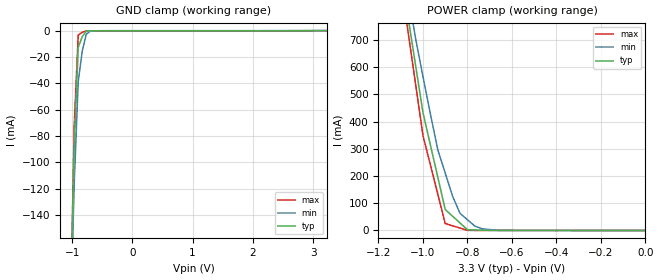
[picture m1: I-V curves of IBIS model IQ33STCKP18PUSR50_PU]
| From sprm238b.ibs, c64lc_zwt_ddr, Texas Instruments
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|   Model Cell IQ33STCKP18PUSR50
[Model]   IQ33STCKP18PUSR50_PU
Model_type   Input
Polarity   Non-Inverting
Vinl =  0.8V
Vinh =  2V
C_comp   0.7641276p   0.7005841p   0.8387284p
[Model Spec]
Vinl   0.8V   0.8V   0.8V
Vinh   2V   2V   2V
[Temperature Range]   25   125   -40
[Voltage Range]   3.3   3.14   3.47
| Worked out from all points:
|   GND clamp passes 1 mA (typ) near -0.78 V on its own axis
|   POWER clamp passes 1 mA (typ) near -0.73 V on its own axis
[POWER_clamp]
|   voltage   I(typ)   I(min)   I(max)
-3.3V     15.05A     13.64A     16.17A
-1.067V   781.2mA    866.5mA    727.6mA
-1.033V   606.9mA    705.9mA    538mA
-1V       432.7mA    564.8mA    348.4mA
-933.3mV  195.4mA    296.2mA    133.1mA
-900mV    76.75mA    210.7mA    25.46mA
-866.7mV  52.11mA    125.2mA    17.11mA
-833.3mV  27.48mA    62.71mA    8.767mA
-800mV    2.836mA    39.32mA    419.2uA
-766.7mV  1.946mA    15.94mA    332.1uA
-733.3mV  1.057mA    5.981mA    245uA
-11.55fV  95.23nA    127.8nA    222.7nA
[GND_clamp]
|   voltage   I(typ)   I(min)   I(max)
-3.3V     -17.3A     -15.65A    -18.51A
-1.033V   -224.7mA   -230.5mA   -227.6mA
-966.7mV  -89.48mA   -116.8mA   -72.36mA
-900mV    -12.72mA   -38.89mA   -3.485mA
-833.3mV  -4.628mA   -15.63mA   -1.34mA
-766.7mV  -440.3uA   -2.832mA   -254uA
-700mV    -155.6uA   -497.2uA   -226.5uA
3.233V    -8.718uA   7.659uA    -45.2uA
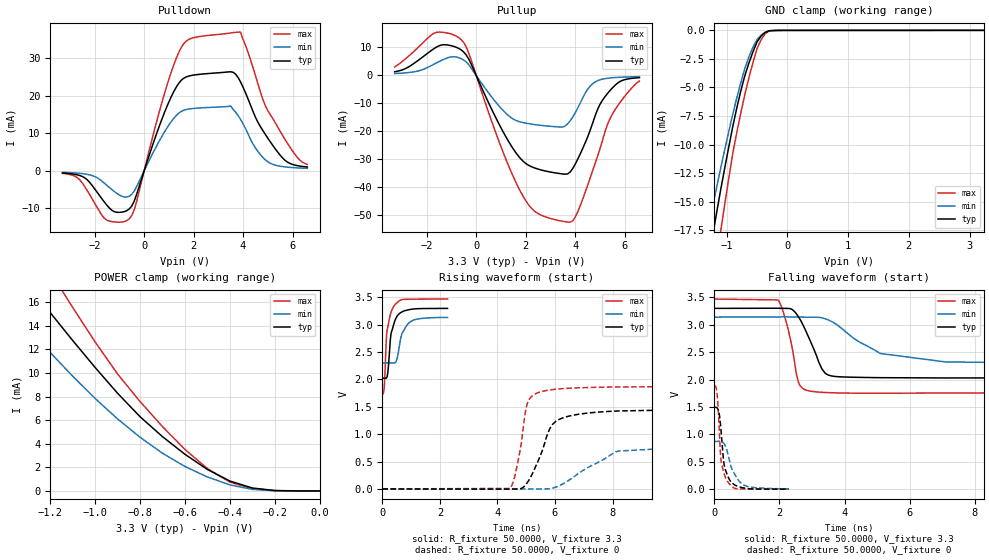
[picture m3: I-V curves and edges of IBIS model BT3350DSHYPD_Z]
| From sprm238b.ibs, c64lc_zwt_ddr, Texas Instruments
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|   Model Cell BT3350DSHYPDFZSCP18
[Model]   BT3350DSHYPD_Z
Model_type   I/O
Polarity   Non-Inverting
Enable   Active-Low
Vinl =  0.8V
Vinh =  2V
Cref =  15.0000pF
Rref =  100.0000M
Vref =  0V
Vmeas =  1.65
C_comp   1.471252p   1.436254p   1.510805p
[Model Spec]
Vinl   0.8V   0.8V   0.8V
Vinh   2V   2V   2V
[Temperature Range]   25   125   -40
[Voltage Range]   3.3   3.14   3.47
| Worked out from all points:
|   slope of the pulldown table from 0 to 0.495 V, typ, clamps not added: 50.8 ohm
|   slope of the pullup table from 0 to 0.495 V, typ, clamps not added: 51.2 ohm
|   GND clamp passes 1 mA (typ) near -0.50 V on its own axis
|   POWER clamp passes 1 mA (typ) near -0.42 V on its own axis
|   rising waveform, R_fixture 50.0000, V_fixture 3.3: 20-80 % time 199ps typ, 278ps min, 162ps max; typ from 2.02 V to 3.3 V
|   rising waveform, R_fixture 50.0000, V_fixture 0: 20-80 % time 704ps typ, 1.65ns min, 350ps max; typ from 0 V to 1.49 V
|   falling waveform, R_fixture 50.0000, V_fixture 3.3: 20-80 % time 549ps typ, 1.47ns min, 355ps max; typ from 3.3 V to 2.04 V
|   falling waveform, R_fixture 50.0000, V_fixture 0: 20-80 % time 187ps typ, 329ps min, 145ps max; typ from 1.49 V to 0.001 V
[POWER_clamp]
|   voltage   I(typ)   I(min)   I(max)
-3.3V     77.67mA    57.5mA     94.63mA
-1.433V   21.11mA    16.7mA     25.79mA
-1.267V   16.76mA    13.13mA    20.62mA
-1.233V   15.94mA    12.43mA    19.6mA
-1.133V   13.55mA    10.4mA     16.57mA
-900mV    8.283mA    6.107mA    9.918mA
-800mV    6.297mA    4.554mA    7.585mA
-600mV    3.11mA     2.075mA    3.521mA
-500mV    1.823mA    1.185mA    1.894mA
-400mV    839.2uA    515.2uA    752.3uA
-300mV    250.4uA    130.7uA    193.1uA
0V        112.2nA    206.3nA    236nA
[Pulldown]
|   voltage   I(typ)   I(min)   I(max)
-3.3V     -544.2uA   -373.8uA   -649.3uA
-2.6V     -1.226mA   -645.1uA   -2.397mA
-1.5V     -9.17mA    -3.874mA   -13.14mA
-600mV    -10.12mA   -6.728mA   -12.73mA
-300mV    -6.174mA   -4.15mA    -8.053mA
900mV     16.8mA     11.19mA    22.28mA
1.5V      24.11mA    15.83mA    32.83mA
3.5V      26.39mA    17.27mA    36.71mA
3.8V      24.86mA    14.73mA    36.94mA
5V        8.732mA    2.435mA    16.05mA
5.8V      2.332mA    999.4uA    7.304mA
6.6V      1.052mA    693.5uA    1.743mA
[Pullup]
|   voltage   I(typ)   I(min)   I(max)
-3.3V     1.324mA    694.3uA    3.024mA
-1.7V     9.62mA     4.052mA    15.11mA
-600mV    9.081mA    5.972mA    12.73mA
1.1V      -20.32mA   -12.63mA   -27.71mA
1.9V      -30.67mA   -16.84mA   -43.22mA
2.5V      -33.44mA   -17.7mA    -49.34mA
3.7V      -35.15mA   -17.28mA   -52.38mA
4.1V      -30.02mA   -11.73mA   -48.83mA
4.6V      -19.78mA   -3.879mA   -36.8mA
5.2V      -7.671mA   -1.145mA   -20.29mA
5.7V      -2.836mA   -700.2uA   -11.11mA
6.6V      -790.1uA   -430.1uA   -2.018mA
[GND_clamp]
|   voltage   I(typ)   I(min)   I(max)
-3.3V     -92.33mA   -69.21mA   -111.6mA
-1.3V     -20.3mA    -17.23mA   -25.02mA
-1.233V   -18.14mA   -15.52mA   -22.55mA
-1.167V   -16.05mA   -13.82mA   -20.11mA
-1.1V     -14.04mA   -12.14mA   -17.68mA
-1.033V   -12.14mA   -10.52mA   -15.33mA
-900mV    -8.477mA   -7.373mA   -10.83mA
-700mV    -3.973mA   -3.332mA   -5.632mA
-500mV    -1.023mA   -808.8uA   -1.617mA
-366.7mV  -182.4uA   -178uA     -312.5uA
-166.7mV  -5.407uA   -6.465uA   -7.339uA
3.233V    80.37nA    2.438uA    206.3nA
[Ramp]
| variable   typ   min   max
dV/dt_f  0.7706559/0.5578093n  0.5145686/1.324064n   1.049533/0.3598343n
dV/dt_r  0.8978218/0.705227n   0.5229636/1.669374n   1.137822/0.3496418n
R_load = 50
[Rising Waveform]
R_fixture = 50.0000
V_fixture = 3.3
V_fixture_min = 3.14
V_fixture_max = 3.47
|   time   V(typ)   V(min)   V(max)
0s        2.024V     2.301V     1.734V
60ps      2.025V     2.303V     1.831V
135ps     2.025V     2.304V     2.705V
165ps     2.051V     2.304V     2.905V
285ps     2.769V     2.303V     3.2V
405ps     3.027V     2.301V     3.343V
510ps     3.155V     2.377V     3.404V
675ps     3.234V     2.828V     3.459V
930ps     3.275V     3.037V     3.467V
2.265ns   3.298V     3.134V     3.47V
[Rising Waveform]
R_fixture = 50.0000
V_fixture = 0
V_fixture_min = 0
V_fixture_max = 0
|   time   V(typ)   V(min)   V(max)
0s        52.07uV    29.49uV    82.73uV
4.425ns   -3.357mV   -74.75uV   9.199mV
4.635ns   -151.3uV   -2.371mV   307.6mV
4.995ns   84.47mV    -1.111mV   1.471V
5.13ns    194.3mV    -533.3uV   1.657V
5.91ns    1.178V     12.48mV    1.815V
7.035ns   1.38V      358.3mV    1.852V
8.175ns   1.425V     691.2mV    1.863V
17.13ns   1.474V     845.3mV    1.877V
115.7ns   1.487V     863.9mV    1.889V
[Falling Waveform]
R_fixture = 50.0000
V_fixture = 3.3
V_fixture_min = 3.14
V_fixture_max = 3.47
|   time   V(typ)   V(min)   V(max)
0s        3.3V       3.14V      3.47V
1.95ns    3.303V     3.143V     3.454V
2.25ns    3.299V     3.145V     2.953V
2.535ns   3.189V     3.141V     2.061V
2.61ns    3.122V     3.141V     1.914V
2.82ns    2.874V     3.14V      1.808V
3.405ns   2.116V     3.11V      1.765V
5.1ns     2.035V     2.477V     1.751V
7.11ns    2.03V      2.322V     1.755V
53.46ns   2.041V     2.291V     1.741V
[Falling Waveform]
R_fixture = 50.0000
V_fixture = 0
V_fixture_min = 0
V_fixture_max = 0
|   time   V(typ)   V(min)   V(max)
0s        1.493V     871.2mV    1.89V
60ps      1.491V     871.7mV    1.832V
90ps      1.477V     872.6mV    1.679V
150ps     1.362V     873.4mV    1.057V
210ps     1.02V      867mV      488.6mV
300ps     438.5mV    826mV      278.3mV
435ps     204.6mV    590.3mV    114.7mV
570ps     99.71mV    326.4mV    32.75mV
900ps     23mV       75.78mV    3.103mV
2.28ns    1.496mV    6.592mV    353.5uV
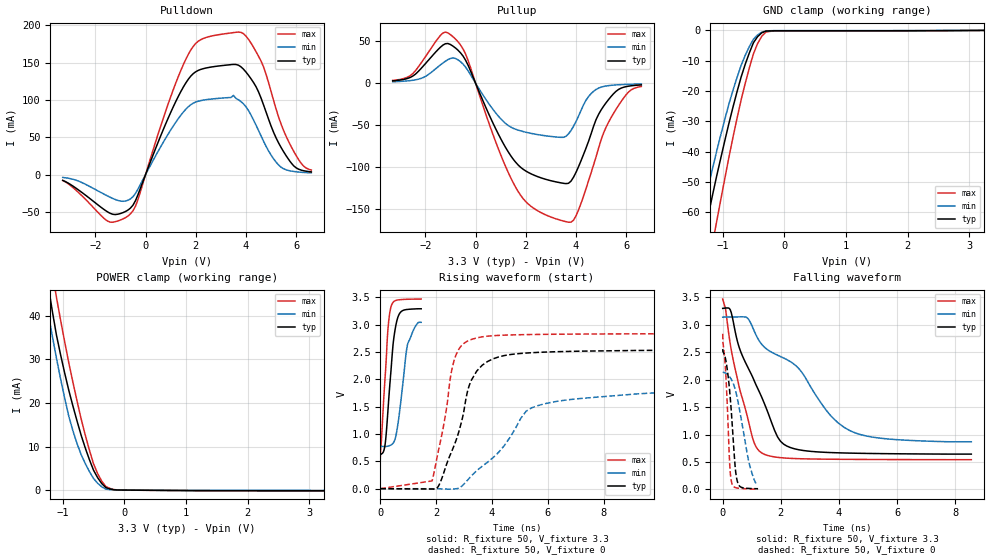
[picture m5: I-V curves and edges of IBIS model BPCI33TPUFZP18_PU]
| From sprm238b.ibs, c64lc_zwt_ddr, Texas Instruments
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|   Model Cell BPCI33TPUFZP18
[Model]   BPCI33TPUFZP18_PU
Model_type   I/O
Polarity   Non-Inverting
Enable   Active-Low
Vinl =  0.8
Vinh =  2.0
Cref =  10.0000pF
Rref =  50.0000
Vref =  1.5V
Vmeas =  1.5
C_comp   3.402036p   3.350014p   3.525193p
[Temperature Range]   25   125   -40
[Voltage Range]   3.3   3.14   3.47
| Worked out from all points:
|   slope of the pulldown table from 0 to 0.495 V, typ, clamps not added: 11.5 ohm
|   slope of the pullup table from 0 to 0.495 V, typ, clamps not added: 14.2 ohm
|   GND clamp passes 1 mA (typ) near -0.38 V on its own axis
|   POWER clamp passes 1 mA (typ) near -0.33 V on its own axis
|   rising waveform, R_fixture 50, V_fixture 3.3: 20-80 % time 250ps typ, 312ps min, 202ps max; typ from 0.62 V to 3.29 V
|   rising waveform, R_fixture 50, V_fixture 0: 20-80 % time 911ps typ, 3.2ns min, 574ps max; typ from 0.001 V to 2.56 V
|   falling waveform, R_fixture 50, V_fixture 3.3: 20-80 % time 1.24ns typ, 2.47ns min, 742ps max; typ from 3.3 V to 0.644 V
|   falling waveform, R_fixture 50, V_fixture 0: 20-80 % time 223ps typ, 423ps min, 145ps max; typ from 2.56 V to 0.014 V
[POWER_clamp]
|   voltage   I(typ)   I(min)   I(max)
-3.3V     268.4mA    207.5mA    327.8mA
-1.3V     53.47mA    45.85mA    64.24mA
-1.233V   47.03mA    40.57mA    56.88mA
-1.167V   41.08mA    35.39mA    50.23mA
-1.1V     35.61mA    30.31mA    44.28mA
-900mV    22.93mA    16.96mA    29.25mA
-700mV    12.61mA    8.149mA    16.37mA
-500mV    4.606mA    2.687mA    6.094mA
-366.7mV  1.523mA    761.7uA    2.069mA
-300mV    577.1uA    229.5uA    834.2uA
-100mV    16.91uA    10.09uA    24.41uA
3.233V    -147.1uA   -77.91uA   -202.4uA
[Pulldown]
|   voltage   I(typ)   I(min)   I(max)
-3.3V     -7.786mA   -3.889mA   -7.984mA
-1.5V     -50.3mA    -28.94mA   -62.59mA
-700mV    -47.57mA   -34.42mA   -55.54mA
-400mV    -34.9mA    -25.14mA   -42.3mA
900mV     75.57mA    54.22mA    94.66mA
1.8V      131.8mA    93.47mA    166.8mA
2.3V      141.8mA    99.68mA    182.3mA
3.7V      146.4mA    100.1mA    190.8mA
4.6V      102.2mA    51.63mA    151.8mA
5.3V      42.12mA    12.63mA    76.7mA
6.1V      7.064mA    3.322mA    19.68mA
6.6V      3.544mA    2.233mA    5.964mA
[Pullup]
|   voltage   I(typ)   I(min)   I(max)
-3.3V     2.841mA    1.735mA    3.327mA
-2.6V     6.941mA    3.146mA    9.055mA
-1.4V     43.04mA    21.88mA    57.16mA
-1V       46.23mA    29.6mA     58.04mA
-400mV    27.62mA    19.3mA     34.95mA
900mV     -60.4mA    -39.07mA   -77.82mA
1.7V      -97.84mA   -56.07mA   -129.6mA
3.7V      -119.6mA   -60.58mA   -166.1mA
4.1V      -99.72mA   -39.32mA   -151.4mA
5.2V      -23.22mA   -3.285mA   -52.37mA
6V        -4.026mA   -1.402mA   -13.57mA
6.6V      -2.032mA   -942.7uA   -3.85mA
[GND_clamp]
|   voltage   I(typ)   I(min)   I(max)
-3.3V     -299.7mA   -234.6mA   -362.3mA
-1.367V   -75.26mA   -63.41mA   -93.68mA
-1.3V     -67.94mA   -57.47mA   -85.74mA
-1.233V   -61.19mA   -51.63mA   -78.23mA
-1.1V     -48.42mA   -40.2mA    -63.49mA
-900mV    -30.88mA   -24.46mA   -42.12mA
-700mV    -15.4mA    -11.56mA   -22.96mA
-500mV    -4.068mA   -2.905mA   -7.714mA
-366.7mV  -816.7uA   -622.7uA   -1.997mA
-300mV    -247.4uA   -192.2uA   -578.9uA
-166.7mV  -146uA     -83.39uA   -214.3uA
3.233V    -8.681uA   10.9uA     -38.06uA
[Ramp]
| variable   typ   min   max
dV/dt_f   1.61148/1.250635n   1.412296/2.566808n   1.763466/0.7446707n
dV/dt_r   1.538312/0.9035575n   1.252299/3.774331n   1.705456/0.5748381n
R_load = 50
[Rising Waveform]
R_fixture = 50
V_fixture = 3.3
V_fixture_min = 3.14
V_fixture_max = 3.47
|   time   V(typ)   V(min)   V(max)
0s        619.9mV    773.3mV    537.3mV
8ps       627.4mV    773.4mV    687.1mV
176ps     822.6mV    773.4mV    2.063V
280ps     1.472V     779.2mV    2.947V
384ps     2.164V     800.1mV    3.325V
488ps     2.767V     855.9mV    3.423V
656ps     3.169V     1.268V     3.453V
976ps     3.278V     2.636V     3.464V
1.264ns   3.288V     2.974V     3.467V
1.464ns   3.29V      3.042V     3.468V
[Rising Waveform]
R_fixture = 50
V_fixture = 0
V_fixture_min = 0
V_fixture_max = 0
|   time   V(typ)   V(min)   V(max)
0s        1.241mV    839.4uV    1.431mV
1.856ns   -4.498mV   193uV      143.8mV
2.12ns    84.69mV    -1.071mV   785.4mV
2.672ns   827.9mV    -1.841mV   2.39V
3.184ns   1.885V     191.2mV    2.713V
3.648ns   2.257V     410.4mV    2.777V
4.44ns    2.435V     787.7mV    2.808V
5.224ns   2.481V     1.419V     2.818V
6.608ns   2.509V     1.619V     2.826V
28.6ns    2.555V     2.041V     2.838V
[Falling Waveform]
R_fixture = 50
V_fixture = 3.3
V_fixture_min = 3.14
V_fixture_max = 3.47
|   time   V(typ)   V(min)   V(max)
0s        3.3V       3.14V      3.47V
96ps      3.307V     3.143V     3.296V
264ps     3.269V     3.143V     2.637V
600ps     2.539V     3.146V     1.795V
1.056ns   2.016V     2.922V     890.7mV
1.328ns   1.698V     2.655V     670.6mV
2.096ns   825.6mV    2.395V     574.6mV
2.624ns   722.8mV    2.2V       560.6mV
4.376ns   662.2mV    1.072V     548.3mV
8.552ns   644.1mV    869.5mV    542.4mV
[Falling Waveform]
R_fixture = 50
V_fixture = 0
V_fixture_min = 0
V_fixture_max = 0
|   time   V(typ)   V(min)   V(max)
0s        2.558V     2.137V     2.838V
8ps       2.51V      2.136V     2.672V
88ps      2.402V     2.123V     2.248V
160ps     2.174V     2.098V     1.505V
240ps     1.789V     2.052V     462.2mV
304ps     1.362V     1.998V     135.3mV
424ps     439.8mV    1.832V     36.28mV
520ps     118.5mV    1.614V     24.03mV
912ps     18.4mV     472.3mV    9.283mV
1.216ns   13.54mV    103.9mV    5.166mV
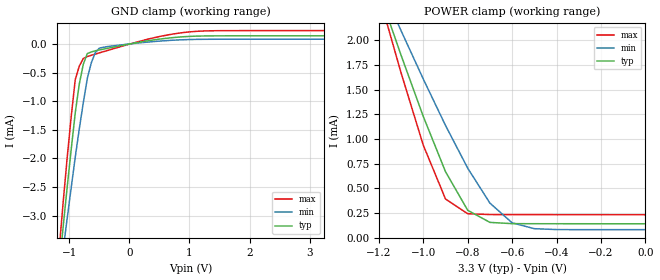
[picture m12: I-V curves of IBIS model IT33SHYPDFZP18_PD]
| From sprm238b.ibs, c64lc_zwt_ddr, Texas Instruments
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|   Model Cell IT33SHYPDFZP18
[Model]   IT33SHYPDFZP18_PD
Model_type   Input
Polarity   Non-Inverting
Vinl =  0.8V
Vinh =  2V
C_comp   0.7732787p   0.7094674p   0.8496547p
[Model Spec]
Vinl   0.8V   0.8V   0.8V
Vinh   2V   2V   2V
[Temperature Range]   25   125   -40
[Voltage Range]   3.3   3.14   3.47
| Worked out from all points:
|   GND clamp passes 1 mA (typ) near -0.87 V on its own axis
|   POWER clamp passes 1 mA (typ) near -0.96 V on its own axis
[POWER_clamp]
|   voltage   I(typ)   I(min)   I(max)
-3.3V     16.3mA     13.43mA    19.08mA
-1.167V   2.281mA    2.432mA    2.197mA
-1.133V   2.065mA    2.265mA    1.934mA
-1.1V     1.849mA    2.097mA    1.671mA
-1V       1.229mA    1.608mA    938.4uA
-900mV    670.2uA    1.138mA    393.7uA
-800mV    279.1uA    705.3uA    244.4uA
-700mV    156.8uA    351.8uA    236uA
-600mV    144uA      152.1uA    235.5uA
-500mV    143.3uA    92.94uA    235.2uA
-400mV    143.1uA    84.12uA    234.9uA
-11.55fV  142.7uA    83.08uA    234uA
[GND_clamp]
|   voltage   I(typ)   I(min)   I(max)
-3.3V     -27.76mA   -22.61mA   -31.33mA
-1.167V   -3.906mA   -4.15mA    -3.581mA
-1.1V     -3.184mA   -3.591mA   -2.758mA
-1.033V   -2.498mA   -3.045mA   -1.979mA
-900mV    -1.206mA   -1.981mA   -623.4uA
-833.3mV  -703.9uA   -1.489mA   -389.3uA
-766.7mV  -357.8uA   -1.031mA   -254.7uA
-700mV    -168.1uA   -606.5uA   -219.8uA
-566.7mV  -119.4uA   -152.2uA   -177.1uA
-500mV    -104.6uA   -72.99uA   -156.2uA
966.7mV   130.3uA    76.27uA    207.4uA
3.233V    142.6uA    83.12uA    233.8uA
